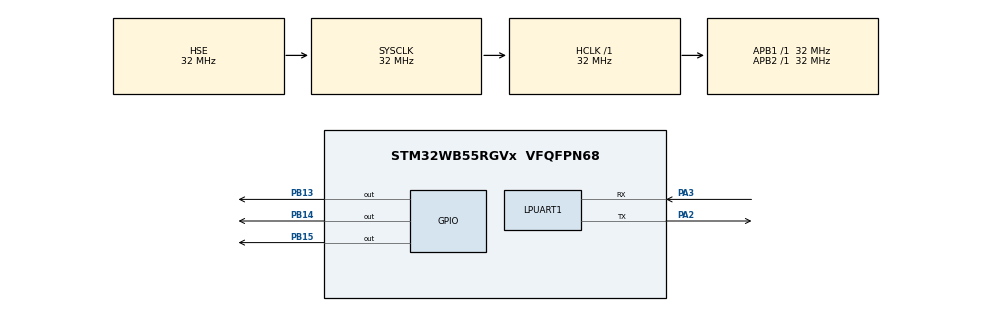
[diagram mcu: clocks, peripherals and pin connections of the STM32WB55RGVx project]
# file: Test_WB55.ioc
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Mcu.Family=STM32WB
Mcu.Name=STM32WB55RGVx
Mcu.Package=VFQFPN68
NVIC.HSEM_IRQn=true\:0\:0\:false\:false\:true\:false\:true\:true
NVIC.IPCC_C1_RX_IRQn=true\:0\:0\:false\:false\:true\:true\:true\:true
NVIC.IPCC_C1_TX_IRQn=true\:0\:0\:false\:false\:true\:true\:true\:true
NVIC.PriorityGroup=NVIC_PRIORITYGROUP_4
OSC_IN.Mode=HSE-External-Oscillator
OSC_IN.Signal=RCC_OSC_IN
OSC_OUT.Mode=HSE-External-Oscillator
OSC_OUT.Signal=RCC_OSC_OUT
PA2.Mode=Asynchronous
PA2.Signal=LPUART1_TX
PA3.Mode=Asynchronous
PA3.Signal=LPUART1_RX
PB13.Signal=GPIO_Output
PB14.Signal=GPIO_Output
PB15.Signal=GPIO_Output
ProjectManager.HeapSize=0x200
ProjectManager.StackSize=0x400
ProjectManager.TargetToolchain=CMake
RCC.ADCFreq_Value=16000000
RCC.AHBFreq_Value=32000000
RCC.APB1Freq_Value=32000000
RCC.APB1TimFreq_Value=32000000
RCC.APB2Freq_Value=32000000
RCC.APB2TimFreq_Value=32000000
RCC.APB3Freq_Value=16000000
RCC.CortexFreq_Value=32000000
RCC.HCLKFreq_Value=32000000
RCC.HSE_VALUE=32000000
RCC.HSI48_VALUE=48000000
RCC.HSI_VALUE=16000000
RCC.LSE_VALUE=32768
RCC.PLLN=32
RCC.SYSCLKFreq_VALUE=32000000
RCC.SYSCLKSource=RCC_SYSCLKSOURCE_HSE
RCC.USBFreq_Value=16000000
RCC.VCOOutputFreq_Value=128000000
RF1.Mode=RF1_Activate
RF1.Signal=RF_RF1
STM32_WPAN.AD_TYPE_COMPLETE_LOCAL_NAME=STM32
STM32_WPAN.AD_TYPE_COMPLETE_LOCAL_NAME_LENGTH=6
STM32_WPAN.BT_SIG_BEACON=Disabled
STM32_WPAN.CFG_DEBUG_APP_TRACE=1
STM32_WPAN.CFG_DEBUG_BLE_TRACE=1
STM32_WPAN.CFG_DEBUG_TRACE_FULL=1
STM32_WPAN.CFG_DEBUG_TRACE_LIGHT=1
STM32_WPAN.CFG_DEBUG_TRACE_UART=hw_lpuart1
STM32_WPAN.CFG_HW_LPUART1_ENABLED=1
STM32_WPAN.CFG_LSCLK_LSE=0
STM32_WPAN.CUSTOM_P2P_SERVER=Disabled
STM32_WPAN.CUSTOM_TEMPLATE=Enabled
STM32_WPAN.INCLUDE_AD_TYPE_128_BIT_SERV_UUID_CMPLT_LIST=1
STM32_WPAN.INCLUDE_AD_TYPE_COMPLETE_LOCAL_NAME=1
STM32_WPAN.INCLUDE_AD_TYPE_TX_POWER_LEVEL=1
STM32_WPAN.NUMBER_OF_SERVICES=1
STM32_WPAN.SERVICE1_CHAR1_LONG_NAME=Test_Value
STM32_WPAN.SERVICE1_CHAR1_PROP_NOTIFY=CHAR_PROP_NOTIFY
STM32_WPAN.SERVICE1_CHAR1_PROP_READ=CHAR_PROP_READ
STM32_WPAN.SERVICE1_CHAR1_SHORT_NAME=Test_Val
STM32_WPAN.SERVICE1_CHAR1_UUID=00 01
STM32_WPAN.SERVICE1_LONG_NAME=My_Service_1
STM32_WPAN.SERVICE1_SHORT_NAME=My_Service
VP_HSEM_VS_HSEM.Mode=HSEM_Activate
VP_IPCC_VS_IPCC.Mode=IPCC_Activate
VP_MEMORYMAP_VS_MEMORYMAP.Mode=CurAppReg
VP_RTC_VS_RTC_Activate.Mode=RTC_Enabled
VP_SEQUENCER_VS_SEQUENCER.Mode=SEQUENCER_Enabled
VP_STM32_WPAN_VS_BLE_HOST.Mode=STM32_WPAN_Enabled
VP_TINY_LPM_VS_TINY_LPM.Mode=TINY_LPM_Enabled
board=custom

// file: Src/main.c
/* USER CODE BEGIN Header */
/**
  ******************************************************************************
  * @file           : main.c
  * @brief          : Main program body
  ******************************************************************************
  * @attention
  *
  * Copyright (c) 2025 STMicroelectronics.
  * All rights reserved.
  *
  * This software is licensed under terms that can be found in the LICENSE file
  * in the root directory of this software component.
  * If no LICENSE file comes with this software, it is provided AS-IS.
  *
  ******************************************************************************
  */
/* USER CODE END Header */
#include "main.h"

IPCC_HandleTypeDef hipcc;

UART_HandleTypeDef hlpuart1;

RTC_HandleTypeDef hrtc;

void SystemClock_Config(void);
void PeriphCommonClock_Config(void);
static void MX_GPIO_Init(void);
static void MX_IPCC_Init(void);
static void MX_LPUART1_UART_Init(void);
static void MX_RTC_Init(void);
static void MX_RF_Init(void);

/* USER CODE BEGIN 0 */
// int _write(int file, char *ptr, int len)
// {
//   HAL_UART_Transmit(&hlpuart1, (uint8_t *)ptr, len, HAL_MAX_DELAY);
//   return len;
// }
/* USER CODE END 0 */

int main(void)
{

  /* MCU Configuration--------------------------------------------------------*/

  /* Reset of all peripherals, Initializes the Flash interface and the Systick. */
  HAL_Init();
  /* Config code for STM32_WPAN (HSE Tuning must be done before system clock configuration) */
  MX_APPE_Config();

  /* Configure the system clock */
  SystemClock_Config();

  /* Configure the peripherals common clocks */
  PeriphCommonClock_Config();

  /* IPCC initialisation */
  MX_IPCC_Init();

  /* Initialize all configured peripherals */
  MX_GPIO_Init();
  MX_LPUART1_UART_Init();
  MX_RTC_Init();
  MX_RF_Init();
  /* USER CODE BEGIN 2 */
  HAL_GPIO_WritePin(GPIOB, GPIO_PIN_1, GPIO_PIN_SET);
  HAL_GPIO_WritePin(GPIOB, GPIO_PIN_0, GPIO_PIN_SET);
  HAL_GPIO_WritePin(GPIOA, GPIO_PIN_4, GPIO_PIN_SET);
  printf("Hello STM32WB55!\r\n");
  /* USER CODE END 2 */

  /* Init code for STM32_WPAN */
  MX_APPE_Init();

  /* Infinite loop */
  while (1)
  {
    MX_APPE_Process();

  }
}

void SystemClock_Config(void)
{
  RCC_OscInitTypeDef RCC_OscInitStruct = {0};
  RCC_ClkInitTypeDef RCC_ClkInitStruct = {0};

  /** Configure the main internal regulator output voltage
  */
  __HAL_PWR_VOLTAGESCALING_CONFIG(PWR_REGULATOR_VOLTAGE_SCALE1);

  /** Initializes the RCC Oscillators according to the specified parameters
  * in the RCC_OscInitTypeDef structure.
  */
  RCC_OscInitStruct.OscillatorType = RCC_OSCILLATORTYPE_HSI|RCC_OSCILLATORTYPE_LSI1
                              |RCC_OSCILLATORTYPE_HSE;
  RCC_OscInitStruct.HSEState = RCC_HSE_ON;
  RCC_OscInitStruct.HSIState = RCC_HSI_ON;
  RCC_OscInitStruct.HSICalibrationValue = RCC_HSICALIBRATION_DEFAULT;
  RCC_OscInitStruct.LSIState = RCC_LSI_ON;
  RCC_OscInitStruct.PLL.PLLState = RCC_PLL_NONE;
  if (HAL_RCC_OscConfig(&RCC_OscInitStruct) != HAL_OK)
  {
    Error_Handler();
  }

  /** Configure the SYSCLKSource, HCLK, PCLK1 and PCLK2 clocks dividers
  */
  RCC_ClkInitStruct.ClockType = RCC_CLOCKTYPE_HCLK4|RCC_CLOCKTYPE_HCLK2
                              |RCC_CLOCKTYPE_HCLK|RCC_CLOCKTYPE_SYSCLK
                              |RCC_CLOCKTYPE_PCLK1|RCC_CLOCKTYPE_PCLK2;
  RCC_ClkInitStruct.SYSCLKSource = RCC_SYSCLKSOURCE_HSE;
  RCC_ClkInitStruct.AHBCLKDivider = RCC_SYSCLK_DIV1;
  RCC_ClkInitStruct.APB1CLKDivider = RCC_HCLK_DIV1;
  RCC_ClkInitStruct.APB2CLKDivider = RCC_HCLK_DIV1;
  RCC_ClkInitStruct.AHBCLK2Divider = RCC_SYSCLK_DIV1;
  RCC_ClkInitStruct.AHBCLK4Divider = RCC_SYSCLK_DIV1;

  if (HAL_RCC_ClockConfig(&RCC_ClkInitStruct, FLASH_LATENCY_1) != HAL_OK)
  {
    Error_Handler();
  }
}

void PeriphCommonClock_Config(void)
{
  RCC_PeriphCLKInitTypeDef PeriphClkInitStruct = {0};

  /** Initializes the peripherals clock
  */
  PeriphClkInitStruct.PeriphClockSelection = RCC_PERIPHCLK_SMPS|RCC_PERIPHCLK_RFWAKEUP;
  PeriphClkInitStruct.RFWakeUpClockSelection = RCC_RFWKPCLKSOURCE_HSE_DIV1024;
  PeriphClkInitStruct.SmpsClockSelection = RCC_SMPSCLKSOURCE_HSI;
  PeriphClkInitStruct.SmpsDivSelection = RCC_SMPSCLKDIV_RANGE1;

  if (HAL_RCCEx_PeriphCLKConfig(&PeriphClkInitStruct) != HAL_OK)
  {
    Error_Handler();
  }
}

static void MX_IPCC_Init(void)
{

  hipcc.Instance = IPCC;
  if (HAL_IPCC_Init(&hipcc) != HAL_OK)
  {
    Error_Handler();
  }

}

static void MX_LPUART1_UART_Init(void)
{

  hlpuart1.Instance = LPUART1;
  hlpuart1.Init.BaudRate = 115200;
  hlpuart1.Init.WordLength = UART_WORDLENGTH_8B;
  hlpuart1.Init.StopBits = UART_STOPBITS_1;
  hlpuart1.Init.Parity = UART_PARITY_NONE;
  hlpuart1.Init.Mode = UART_MODE_TX_RX;
  hlpuart1.Init.HwFlowCtl = UART_HWCONTROL_NONE;
  hlpuart1.Init.OneBitSampling = UART_ONE_BIT_SAMPLE_DISABLE;
  hlpuart1.Init.ClockPrescaler = UART_PRESCALER_DIV1;
  hlpuart1.AdvancedInit.AdvFeatureInit = UART_ADVFEATURE_NO_INIT;
  hlpuart1.FifoMode = UART_FIFOMODE_DISABLE;
  if (HAL_UART_Init(&hlpuart1) != HAL_OK)
  {
    Error_Handler();
  }
  if (HAL_UARTEx_SetTxFifoThreshold(&hlpuart1, UART_TXFIFO_THRESHOLD_1_8) != HAL_OK)
  {
    Error_Handler();
  }
  if (HAL_UARTEx_SetRxFifoThreshold(&hlpuart1, UART_RXFIFO_THRESHOLD_1_8) != HAL_OK)
  {
    Error_Handler();
  }
  if (HAL_UARTEx_DisableFifoMode(&hlpuart1) != HAL_OK)
  {
    Error_Handler();
  }

}

static void MX_RF_Init(void)
{

}

static void MX_RTC_Init(void)
{

  /** Initialize RTC Only
  */
  hrtc.Instance = RTC;
  hrtc.Init.HourFormat = RTC_HOURFORMAT_24;
  hrtc.Init.AsynchPrediv = CFG_RTC_ASYNCH_PRESCALER;
  hrtc.Init.SynchPrediv = CFG_RTC_SYNCH_PRESCALER;
  hrtc.Init.OutPut = RTC_OUTPUT_DISABLE;
  hrtc.Init.OutPutPolarity = RTC_OUTPUT_POLARITY_HIGH;
  hrtc.Init.OutPutType = RTC_OUTPUT_TYPE_OPENDRAIN;
  hrtc.Init.OutPutRemap = RTC_OUTPUT_REMAP_NONE;
  if (HAL_RTC_Init(&hrtc) != HAL_OK)
  {
    Error_Handler();
  }

}

static void MX_GPIO_Init(void)
{
  GPIO_InitTypeDef GPIO_InitStruct = {0};

  /* GPIO Ports Clock Enable */
  __HAL_RCC_GPIOA_CLK_ENABLE();
  __HAL_RCC_GPIOB_CLK_ENABLE();

  /*Configure GPIO pin Output Level */
  HAL_GPIO_WritePin(GPIOB, GPIO_PIN_0|GPIO_PIN_1, GPIO_PIN_RESET);
  HAL_GPIO_WritePin(GPIOA, GPIO_PIN_4, GPIO_PIN_RESET);
  /*Configure GPIO pins : PB0 PB1 PA4 */
  GPIO_InitStruct.Pin = GPIO_PIN_0|GPIO_PIN_1;
  GPIO_InitStruct.Mode = GPIO_MODE_OUTPUT_PP;
  GPIO_InitStruct.Pull = GPIO_NOPULL;
  GPIO_InitStruct.Speed = GPIO_SPEED_FREQ_LOW;
  HAL_GPIO_Init(GPIOB, &GPIO_InitStruct);

  GPIO_InitStruct.Pin = GPIO_PIN_4;
  GPIO_InitStruct.Mode = GPIO_MODE_OUTPUT_PP;
  GPIO_InitStruct.Pull = GPIO_NOPULL;
  GPIO_InitStruct.Speed = GPIO_SPEED_FREQ_LOW;
  HAL_GPIO_Init(GPIOA, &GPIO_InitStruct);

}

void Error_Handler(void)
{
  /* USER CODE BEGIN Error_Handler_Debug */
  printf("Error occurred!\r\n");
  /* User can add his own implementation to report the HAL error return state */
  __disable_irq();
  while (1)
  {
  }
  /* USER CODE END Error_Handler_Debug */
}
